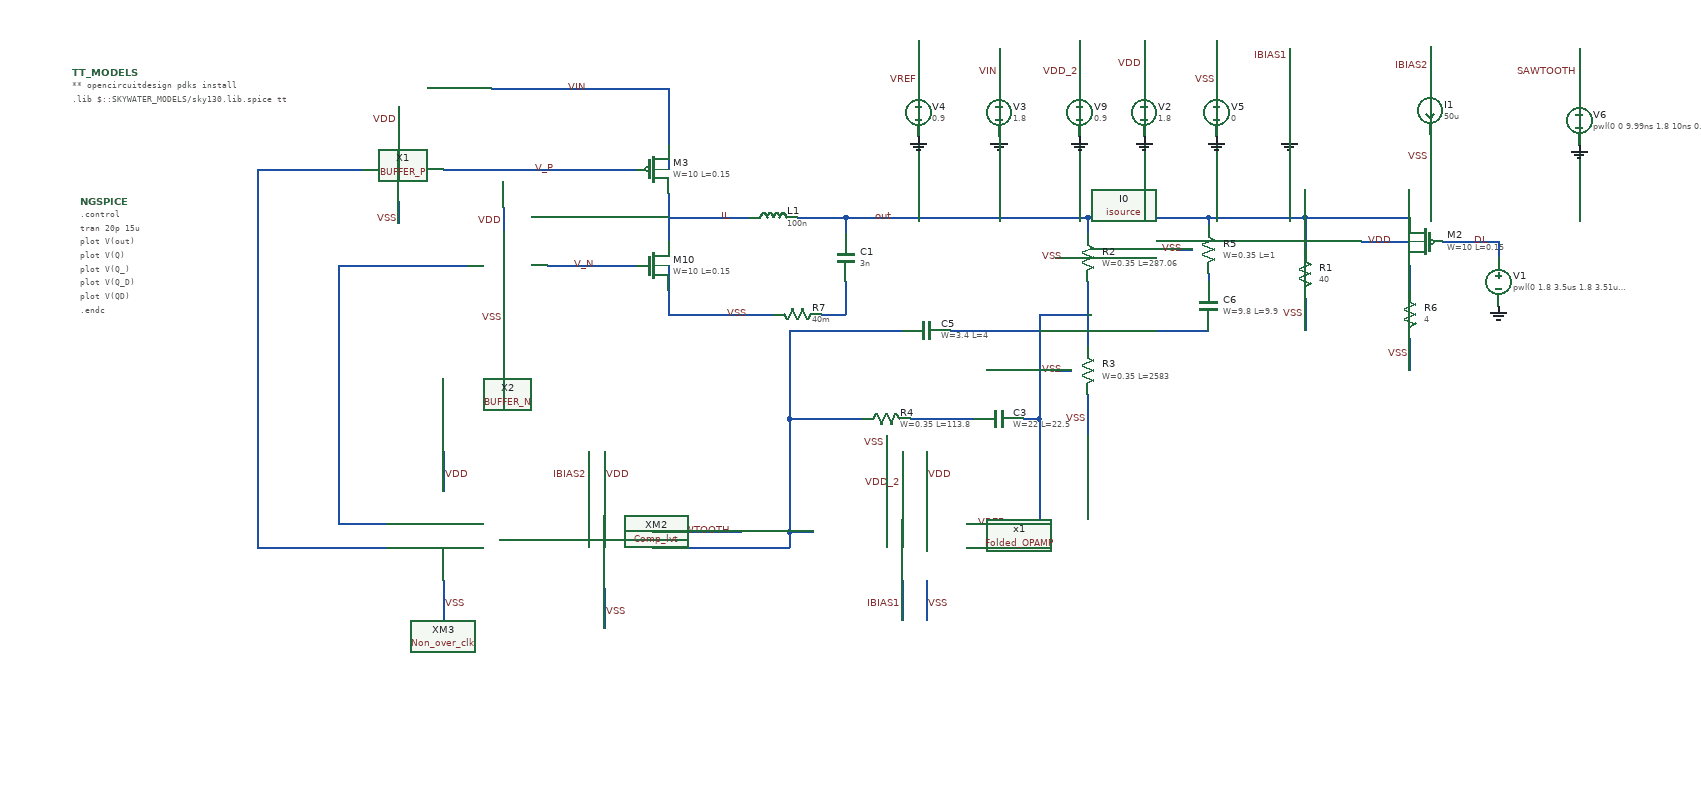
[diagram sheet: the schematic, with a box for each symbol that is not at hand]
v {xschem version=3.0.0 file_version=1.2 }
G {}
K {}
V {}
S {}
E {}
N 1830 -900 1830 -840 {
lab=IL}
N 1830 -960 1830 -930 {
lab=VIN}
N 1740 -930 1790 -930 {
lab=V_P}
N 1830 -1030 1830 -960 {
lab=VIN}
N 1610 -1030 1830 -1030 {
lab=VIN}
N 1830 -780 1830 -750 {
lab=VSS}
N 1830 -870 1890 -870 {
lab=IL}
N 1890 -870 1930 -870 {
lab=IL}
N 2050 -870 2050 -850 {
lab=out}
N 1990 -870 2050 -870 {
lab=out}
N 2050 -790 2050 -750 {
lab=#net1}
N 2050 -870 2160 -870 {
lab=out}
N 2150 -580 2150 -530 {
lab=VDD}
N 2120 -580 2120 -530 {
lab=VDD_2}
N 2150 -420 2150 -370 {
lab=VSS}
N 2120 -420 2120 -370 {
lab=IBIAS1}
N 2200 -460 2250 -460 {
lab=#net2}
N 2200 -490 2250 -490 {
lab=VREF}
N 2240 -1080 2240 -1030 {
lab=VIN}
N 2340 -1090 2340 -1030 {
lab=VDD_2}
N 2420 -1040 2420 -1030 {
lab=VDD}
N 2420 -1090 2420 -1040 {
lab=VDD}
N 2510 -1060 2510 -1040 {
lab=VSS}
N 2510 -1040 2510 -1030 {
lab=VSS}
N 2510 -1090 2510 -1060 {
lab=VSS}
N 2600 -1080 2600 -1020 {
lab=IBIAS1}
N 1750 -580 1750 -530 {
lab=VDD}
N 1750 -410 1750 -360 {
lab=VSS}
N 2140 -1060 2140 -1040 {
lab=VREF}
N 2140 -1040 2140 -1030 {
lab=VREF}
N 2140 -1090 2140 -1060 {
lab=VREF}
N 2250 -460 2280 -460 {
lab=#net2}
N 2775 -972.5 2775 -922.5 {
lab=VSS}
N 1730 -580 1730 -530 {
lab=IBIAS2}
N 2960 -1080 2960 -1020 {
lab=SAWTOOTH}
N 1550 -930 1740 -930 {
lab=V_P}
N 2160 -870 2340 -870 {
lab=out}
N 2350 -870 2350 -850 {
lab=out}
N 2350 -790 2350 -740 {
lab=#net2}
N 2350 -650 2350 -600 {
lab=VSS}
N 2130 -620 2210 -620 {
lab=#net3}
N 1980 -620 2070 -620 {
lab=#net4}
N 1980 -620 1980 -480 {
lab=#net4}
N 2290 -620 2290 -490 {
lab=#net2}
N 2270 -620 2290 -620 {
lab=#net2}
N 1980 -730 2120 -730 {
lab=#net4}
N 2180 -730 2290 -730 {
lab=#net2}
N 2290 -690 2290 -620 {
lab=#net2}
N 1980 -480 2010 -480 {
lab=#net4}
N 2290 -490 2290 -460 {
lab=#net2}
N 2280 -460 2290 -460 {
lab=#net2}
N 2350 -870 2500 -870 {
lab=out}
N 2500 -870 2500 -860 {
lab=out}
N 2500 -800 2500 -790 {
lab=#net5}
N 2340 -870 2350 -870 {
lab=out}
N 2290 -750 2290 -690 {
lab=#net2}
N 2290 -750 2350 -750 {
lab=#net2}
N 2350 -740 2350 -710 {
lab=#net2}
N 2620 -870 2620 -830 {
lab=out}
N 2500 -870 2620 -870 {
lab=out}
N 2620 -770 2620 -730 {
lab=VSS}
N 1810 -460 1980 -460 {
lab=#net4}
N 1980 -480 1980 -460 {
lab=#net4}
N 1740 -810 1790 -810 {
lab=V_N}
N 1830 -810 1830 -780 {
lab=VSS}
N 2620 -870 2750 -870 {
lab=out}
N 2750 -720 2750 -680 {
lab=VSS}
N 2750 -810 2750 -780 {
lab=#net6}
N 2790 -840 2860 -840 {
lab=DL}
N 2860 -840 2860 -820 {
lab=DL}
N 1550 -580 1550 -530 {
lab=VDD}
N 1550 -420 1550 -370 {
lab=VSS}
N 1320 -930 1450 -930 {
lab=#net7}
N 1320 -930 1320 -490 {
lab=#net7}
N 1495 -890 1495 -862.5 {
lab=VSS}
N 1495 -1007.5 1495 -972.5 {
lab=VDD}
N 1680 -810 1740 -810 {
lab=V_N}
N 1420 -810 1580 -810 {
lab=#net8}
N 1420 -810 1420 -720 {
lab=#net8}
N 1625 -770 1625 -732.5 {
lab=VSS}
N 1625 -882.5 1625 -852.5 {
lab=VDD}
N 1420 -490 1480 -490 {
lab=#net8}
N 1420 -720 1420 -490 {
lab=#net8}
N 1320 -460 1480 -460 {
lab=#net7}
N 1320 -490 1320 -460 {
lab=#net7}
N 1980 -730 1980 -620 {
lab=#net4}
N 2350 -730 2400 -730 {
lab=#net2}
N 2400 -730 2500 -730 {
lab=#net2}
N 2150 -420 2150 -370 {
lab=VSS}
N 2690 -840 2750 -840 {
lab=VDD}
N 2775 -1082.5 2775 -1032.5 {
lab=IBIAS2}
N 1630 -470 1680 -470 {
lab=#net9}
N 1810 -480 1920 -480 {
lab=SAWTOOTH}
N 2100 -600 2100 -580 {
lab=VSS}
N 2460 -830 2480 -830 {
lab=VSS}
N 2310 -820 2330 -820 {
lab=VSS}
N 2310 -680 2330 -680 {
lab=VSS}
N 1830 -750 1960 -750 {
lab=VSS}
N 2020 -750 2050 -750 {
lab=#net1}
N 1620 -470 1630 -470 {
lab=#net9}
C {sky130_fd_pr/pfet_01v8.sym} 1810 -930 0 0 {name=M3
L=0.15
W=10
nf=1
mult=450
ad="'int((nf+1)/2) * W/nf * 0.29'" 
pd="'2*int((nf+1)/2) * (W/nf + 0.29)'"
as="'int((nf+2)/2) * W/nf * 0.29'" 
ps="'2*int((nf+2)/2) * (W/nf + 0.29)'"
nrd="'0.29 / W'" nrs="'0.29 / W'"
sa=0 sb=0 sd=0
model=pfet_01v8
spiceprefix=X
}
C {devices/ind.sym} 1960 -870 3 0 {name=L1
m=1
value=100n
footprint=1206
device=inductor}
C {devices/capa.sym} 2050 -820 0 0 {name=C1
m=1
value=3n
footprint=1206
device="ceramic capacitor"}
C {devices/code.sym} 1090 -1050 0 0 {name=TT_MODELS
only_toplevel=true
format="tcleval( @value )"
value="
** opencircuitdesign pdks install
.lib $::SKYWATER_MODELS/sky130.lib.spice tt

"
spice_ignore=false}
C {devices/code_shown.sym} 1100 -890 0 0 {name=NGSPICE
only_toplevel=true
value="

.control

tran 20p 15u
plot V(out)
plot V(Q)
plot V(Q_) 
plot V(Q_D)
plot V(QD)
.endc
" }
C {devices/lab_wire.sym} 2110 -870 0 0 {name=l4 sig_type=std_logic lab=out}
C {devices/lab_wire.sym} 1910 -870 0 0 {name=l6 sig_type=std_logic lab=IL}
C {devices/lab_wire.sym} 1730 -1030 0 0 {name=l5 sig_type=std_logic lab=VIN}
C {devices/vsource.sym} 2240 -1000 0 0 {name=V3 value=1.8}
C {devices/gnd.sym} 2240 -970 0 0 {name=l7 lab=GND}
C {devices/lab_wire.sym} 2240 -1050 0 0 {name=l2 sig_type=std_logic lab=VIN}
C {devices/gnd.sym} 2600 -970 0 0 {name=l19 lab=GND}
C {devices/lab_wire.sym} 2600 -1070 0 0 {name=l22 sig_type=std_logic lab=IBIAS1}
C {devices/isource.sym} 2600 -1000 0 0 {name=I0 value=50u}
C {devices/vsource.sym} 2340 -1000 0 0 {name=V9 value=0.9}
C {devices/gnd.sym} 2340 -970 0 0 {name=l42 lab=GND}
C {devices/lab_wire.sym} 2340 -1050 0 0 {name=l8 sig_type=std_logic lab=VDD_2}
C {devices/vsource.sym} 2420 -1000 0 0 {name=V2 value=1.8}
C {devices/gnd.sym} 2420 -970 0 0 {name=l18 lab=GND}
C {devices/vsource.sym} 2510 -1000 0 0 {name=V5 value=0}
C {devices/gnd.sym} 2510 -970 0 0 {name=l26 lab=GND}
C {devices/lab_wire.sym} 2510 -1040 0 0 {name=l10 sig_type=std_logic lab=VSS}
C {devices/lab_wire.sym} 2150 -550 0 1 {name=l13 sig_type=std_logic lab=VDD}
C {devices/lab_wire.sym} 2120 -540 0 0 {name=l14 sig_type=std_logic lab=VDD_2}
C {devices/lab_wire.sym} 1930 -750 0 0 {name=l1 sig_type=std_logic lab=VSS}
C {devices/lab_wire.sym} 2150 -390 0 1 {name=l15 sig_type=std_logic lab=VSS}
C {devices/lab_wire.sym} 2120 -390 0 0 {name=l16 sig_type=std_logic lab=IBIAS1}
C {devices/lab_wire.sym} 1750 -550 0 1 {name=l11 sig_type=std_logic lab=VDD}
C {devices/lab_wire.sym} 1750 -380 0 1 {name=l12 sig_type=std_logic lab=VSS}
C {devices/vsource.sym} 2140 -1000 0 0 {name=V4 value=0.9}
C {devices/gnd.sym} 2140 -970 0 0 {name=l17 lab=GND}
C {devices/lab_wire.sym} 2140 -1040 0 0 {name=l20 sig_type=std_logic lab=VREF}
C {devices/isource.sym} 2775 -1002.5 0 1 {name=I1 value=50u}
C {devices/lab_wire.sym} 1730 -550 0 0 {name=l27 sig_type=std_logic lab=IBIAS2}
C {devices/vsource.sym} 2960 -990 0 0 {name=V6 value="pwl(0 0 9.99ns 1.8 10ns 0) r=0"}
C {devices/gnd.sym} 2960 -960 0 0 {name=l28 lab=GND}
C {devices/gnd.sym} 2960 -960 0 0 {name=l29 lab=GND}
C {devices/lab_wire.sym} 2960 -1050 0 0 {name=l30 sig_type=std_logic lab=SAWTOOTH}
C {devices/lab_wire.sym} 2350 -620 0 0 {name=l31 sig_type=std_logic lab=VSS}
C {devices/lab_wire.sym} 2250 -490 0 0 {name=l33 sig_type=std_logic lab=VREF}
C {devices/lab_wire.sym} 1910 -480 0 0 {name=l32 sig_type=std_logic lab=SAWTOOTH}
C {devices/lab_wire.sym} 2620 -750 0 0 {name=l21 sig_type=std_logic lab=VSS}
C {sky130_fd_pr/pfet_01v8.sym} 2770 -840 0 1 {name=M2
L=0.15
W=10
nf=1
mult=450
ad="'int((nf+1)/2) * W/nf * 0.29'" 
pd="'2*int((nf+1)/2) * (W/nf + 0.29)'"
as="'int((nf+2)/2) * W/nf * 0.29'" 
ps="'2*int((nf+2)/2) * (W/nf + 0.29)'"
nrd="'0.29 / W'" nrs="'0.29 / W'"
sa=0 sb=0 sd=0
model=pfet_01v8
spiceprefix=X
}
C {devices/lab_wire.sym} 2750 -700 0 0 {name=l23 sig_type=std_logic lab=VSS}
C {devices/vsource.sym} 2860 -790 0 0 {name=V1 value="pwl(0 1.8 3.5us 1.8 3.51us 0 7us 0) r=0"}
C {devices/gnd.sym} 2860 -760 0 0 {name=l34 lab=GND}
C {devices/gnd.sym} 2860 -760 0 0 {name=l36 lab=GND}
C {devices/lab_wire.sym} 1550 -550 0 1 {name=l35 sig_type=std_logic lab=VDD}
C {devices/lab_wire.sym} 1550 -390 0 1 {name=l37 sig_type=std_logic lab=VSS}
C {DC_DC_Converter/BUFFER/BUFFER_PMOS/BUFFER_P.sym} 1430 -880 0 0 {name=X1}
C {devices/lab_wire.sym} 1495 -990 0 0 {name=l38 sig_type=std_logic lab=VDD}
C {devices/lab_wire.sym} 1495 -867.5 0 0 {name=l40 sig_type=std_logic lab=VSS}
C {DC_DC_Converter/BUFFER/BUFFER_NMOS/BUFFER_N.sym} 1490 -730 0 0 {name=X2}
C {devices/lab_wire.sym} 1625 -745 0 0 {name=l39 sig_type=std_logic lab=VSS}
C {devices/lab_wire.sym} 1625 -865 0 0 {name=l41 sig_type=std_logic lab=VDD}
C {DC_DC_Converter/Non_Overlap_Clk/Non_over_clk.sym} 1750 -210 0 1 {name=XM3}
C {devices/lab_wire.sym} 1690 -930 0 0 {name=l3 sig_type=std_logic lab=V_P}
C {devices/lab_wire.sym} 1740 -810 0 0 {name=l43 sig_type=std_logic lab=V_N}
C {devices/lab_wire.sym} 2850 -840 0 0 {name=l96 sig_type=std_logic lab=DL}
C {sky130_fd_pr/cap_mim_m3_1.sym} 2150 -730 3 0 {name=C5 model=cap_mim_m3_1 W=3.4 L=4 MF=1 spiceprefix=X}
C {sky130_fd_pr/cap_mim_m3_1.sym} 2240 -620 3 0 {name=C3 model=cap_mim_m3_1 W=22 L=22.5 MF=1 spiceprefix=X}
C {sky130_fd_pr/cap_mim_m3_1.sym} 2500 -760 0 0 {name=C6 model=cap_mim_m3_1 W=9.8 L=9.9 MF=1 spiceprefix=X}
C {devices/lab_wire.sym} 2420 -1060 0 0 {name=l97 sig_type=std_logic lab=VDD}
C {devices/lab_wire.sym} 2730 -840 0 0 {name=l98 sig_type=std_logic lab=VDD}
C {sky130_fd_pr/nfet_01v8.sym} 1810 -810 0 0 {name=M10
L=0.15
W=10
nf=1 
mult=150
ad="'int((nf+1)/2) * W/nf * 0.29'" 
pd="'2*int((nf+1)/2) * (W/nf + 0.29)'"
as="'int((nf+2)/2) * W/nf * 0.29'" 
ps="'2*int((nf+2)/2) * (W/nf + 0.29)'"
nrd="'0.29 / W'" nrs="'0.29 / W'"
sa=0 sb=0 sd=0
model=nfet_01v8
spiceprefix=X
}
C {devices/lab_wire.sym} 2775 -1057.5 0 0 {name=l24 sig_type=std_logic lab=IBIAS2}
C {devices/lab_wire.sym} 2775 -945 0 0 {name=l25 sig_type=std_logic lab=VSS}
C {sky130_fd_pr/res_high_po_0p35.sym} 2100 -620 3 0 {name=R4
W=0.35
L=113.8
model=res_high_po_0p35
spiceprefix=X
mult=1}
C {devices/lab_wire.sym} 2100 -590 3 0 {name=l9 sig_type=std_logic lab=VSS}
C {sky130_fd_pr/res_high_po_0p35.sym} 2500 -830 0 0 {name=R5
W=0.35
L=1
model=res_high_po_0p35
spiceprefix=X
mult=1}
C {devices/lab_wire.sym} 2470 -830 0 0 {name=l44 sig_type=std_logic lab=VSS}
C {sky130_fd_pr/res_high_po_0p35.sym} 2350 -820 0 0 {name=R2
W=0.35
L=287.06
model=res_high_po_0p35
spiceprefix=X
mult=1}
C {devices/lab_wire.sym} 2320 -820 0 0 {name=l45 sig_type=std_logic lab=VSS}
C {sky130_fd_pr/res_high_po_0p35.sym} 2350 -680 0 0 {name=R3
W=0.35
L=2583
model=res_high_po_0p35
spiceprefix=X
mult=1}
C {devices/lab_wire.sym} 2320 -680 0 0 {name=l46 sig_type=std_logic lab=VSS}
C {devices/res.sym} 1990 -750 1 0 {name=R7
value=40m
footprint=1206
device=resistor
m=1}
C {devices/res.sym} 2620 -800 0 0 {name=R1
value=40
footprint=1206
device=resistor
m=1}
C {devices/res.sym} 2750 -750 0 0 {name=R6
value=4
footprint=1206
device=resistor
m=1}
C {DC_DC_Converter/Comparator/Comp_lvt.sym} 1830 -400 0 1 {name=XM2}
C {OTHERS/DC_DC_Converter_V7/Folded_OPAMP/Folded_OPAMP.sym} 2340 -310 0 1 {name=x1}
